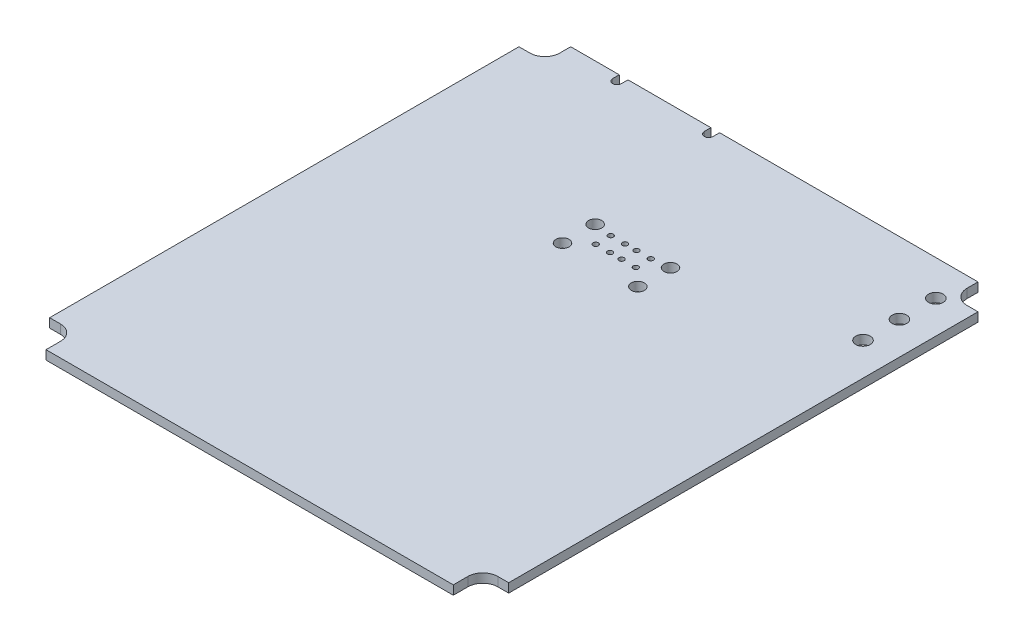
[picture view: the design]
ISO-10303-21;
HEADER;
FILE_DESCRIPTION(('STEP AP214'),'2;1');
FILE_NAME('part.step','',(''),(''),'','','');
FILE_SCHEMA(('AUTOMOTIVE_DESIGN { 1 0 10303 214 1 1 1 1 }'));
ENDSEC;
DATA;
#1=APPLICATION_CONTEXT('core data for automotive mechanical design processes');
#2=APPLICATION_PROTOCOL_DEFINITION('international standard','automotive_design',2000,#1);
#3=PRODUCT_CONTEXT('',#1,'mechanical');
#4=PRODUCT('Part','Part','',(#3));
#5=PRODUCT_RELATED_PRODUCT_CATEGORY('part','',(#4));
#6=PRODUCT_DEFINITION_FORMATION('','',#4);
#7=PRODUCT_DEFINITION_CONTEXT('part definition',#1,'design');
#8=PRODUCT_DEFINITION('design','',#6,#7);
#9=PRODUCT_DEFINITION_SHAPE('','',#8);
#10=(LENGTH_UNIT() NAMED_UNIT(*) SI_UNIT(.MILLI.,.METRE.));
#11=(NAMED_UNIT(*) PLANE_ANGLE_UNIT() SI_UNIT($,.RADIAN.));
#12=(NAMED_UNIT(*) SI_UNIT($,.STERADIAN.) SOLID_ANGLE_UNIT());
#13=UNCERTAINTY_MEASURE_WITH_UNIT(LENGTH_MEASURE(1.E-05),#10,'distance_accuracy_value','');
#14=(GEOMETRIC_REPRESENTATION_CONTEXT(3) GLOBAL_UNCERTAINTY_ASSIGNED_CONTEXT((#13)) GLOBAL_UNIT_ASSIGNED_CONTEXT((#10,
#11,#12)) REPRESENTATION_CONTEXT('',''));
#15=CARTESIAN_POINT('',(0.,0.,0.));
#16=DIRECTION('',(0.,0.,1.));
#17=DIRECTION('',(1.,0.,0.));
#18=AXIS2_PLACEMENT_3D('',#15,#16,#17);
#19=CARTESIAN_POINT('',(-39.99992,0.,45.72));
#20=DIRECTION('',(0.,1.,0.));
#21=DIRECTION('',(0.,0.,1.));
#22=AXIS2_PLACEMENT_3D('',#19,#20,#21);
#23=PLANE('',#22);
#24=DIRECTION('',(1.,0.,0.));
#25=VECTOR('',#24,1.);
#26=CARTESIAN_POINT('',(38.09492,0.,-41.2115));
#27=LINE('',#26,#25);
#28=CARTESIAN_POINT('',(38.09492,0.,-41.2115));
#29=VERTEX_POINT('',#28);
#30=CARTESIAN_POINT('',(39.99992,0.,-41.2115));
#31=VERTEX_POINT('',#30);
#32=EDGE_CURVE('E212',#29,#31,#27,.T.);
#33=ORIENTED_EDGE('',*,*,#32,.T.);
#34=DIRECTION('',(0.,0.,1.));
#35=VECTOR('',#34,1.);
#36=CARTESIAN_POINT('',(39.99992,0.,-45.72));
#37=LINE('',#36,#35);
#38=CARTESIAN_POINT('',(39.99992,0.,40.5765));
#39=VERTEX_POINT('',#38);
#40=EDGE_CURVE('E206',#31,#39,#37,.T.);
#41=ORIENTED_EDGE('',*,*,#40,.T.);
#42=DIRECTION('',(-1.,0.,0.));
#43=VECTOR('',#42,1.);
#44=CARTESIAN_POINT('',(44.3342036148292,0.,40.5765));
#45=LINE('',#44,#43);
#46=CARTESIAN_POINT('',(38.09492,0.,40.5765));
#47=VERTEX_POINT('',#46);
#48=EDGE_CURVE('E216',#39,#47,#45,.T.);
#49=ORIENTED_EDGE('',*,*,#48,.T.);
#50=CARTESIAN_POINT('',(38.09492,0.,43.18));
#51=DIRECTION('',(0.,1.,0.));
#52=DIRECTION('',(0.,0.,1.));
#53=AXIS2_PLACEMENT_3D('',#50,#51,#52);
#54=CIRCLE('',#53,2.6035);
#55=CARTESIAN_POINT('',(35.49142,0.,43.18));
#56=VERTEX_POINT('',#55);
#57=EDGE_CURVE('E367',#47,#56,#54,.T.);
#58=ORIENTED_EDGE('',*,*,#57,.T.);
#59=DIRECTION('',(0.,0.,1.));
#60=VECTOR('',#59,1.);
#61=CARTESIAN_POINT('',(35.49142,0.,43.18));
#62=LINE('',#61,#60);
#63=CARTESIAN_POINT('',(35.49142,0.,45.72));
#64=VERTEX_POINT('',#63);
#65=EDGE_CURVE('E221',#56,#64,#62,.T.);
#66=ORIENTED_EDGE('',*,*,#65,.T.);
#67=DIRECTION('',(-1.,0.,0.));
#68=VECTOR('',#67,1.);
#69=CARTESIAN_POINT('',(-39.99992,0.,45.72));
#70=LINE('',#69,#68);
#71=CARTESIAN_POINT('',(-35.49142,0.,45.72));
#72=VERTEX_POINT('',#71);
#73=EDGE_CURVE('E224',#64,#72,#70,.T.);
#74=ORIENTED_EDGE('',*,*,#73,.T.);
#75=DIRECTION('',(0.,0.,-1.));
#76=VECTOR('',#75,1.);
#77=CARTESIAN_POINT('',(-35.49142,0.,43.18));
#78=LINE('',#77,#76);
#79=CARTESIAN_POINT('',(-35.49142,0.,43.18));
#80=VERTEX_POINT('',#79);
#81=EDGE_CURVE('E232',#72,#80,#78,.T.);
#82=ORIENTED_EDGE('',*,*,#81,.T.);
#83=CARTESIAN_POINT('',(-38.09492,0.,43.18));
#84=DIRECTION('',(0.,1.,0.));
#85=DIRECTION('',(0.,0.,1.));
#86=AXIS2_PLACEMENT_3D('',#83,#84,#85);
#87=CIRCLE('',#86,2.6035);
#88=CARTESIAN_POINT('',(-38.09492,0.,40.5765));
#89=VERTEX_POINT('',#88);
#90=EDGE_CURVE('E369',#80,#89,#87,.T.);
#91=ORIENTED_EDGE('',*,*,#90,.T.);
#92=DIRECTION('',(-1.,0.,0.));
#93=VECTOR('',#92,1.);
#94=CARTESIAN_POINT('',(-43.8329095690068,0.,40.5765));
#95=LINE('',#94,#93);
#96=CARTESIAN_POINT('',(-39.99992,0.,40.5765));
#97=VERTEX_POINT('',#96);
#98=EDGE_CURVE('E238',#89,#97,#95,.T.);
#99=ORIENTED_EDGE('',*,*,#98,.T.);
#100=DIRECTION('',(0.,0.,-1.));
#101=VECTOR('',#100,1.);
#102=CARTESIAN_POINT('',(-39.99992,0.,-45.72));
#103=LINE('',#102,#101);
#104=CARTESIAN_POINT('',(-39.99992,0.,-41.2115));
#105=VERTEX_POINT('',#104);
#106=EDGE_CURVE('E241',#97,#105,#103,.T.);
#107=ORIENTED_EDGE('',*,*,#106,.T.);
#108=DIRECTION('',(1.,0.,0.));
#109=VECTOR('',#108,1.);
#110=CARTESIAN_POINT('',(-38.09492,0.,-41.2115));
#111=LINE('',#110,#109);
#112=CARTESIAN_POINT('',(-38.09492,0.,-41.2115));
#113=VERTEX_POINT('',#112);
#114=EDGE_CURVE('E249',#105,#113,#111,.T.);
#115=ORIENTED_EDGE('',*,*,#114,.T.);
#116=CARTESIAN_POINT('',(-38.09492,0.,-43.815));
#117=DIRECTION('',(0.,1.,0.));
#118=DIRECTION('',(0.,0.,1.));
#119=AXIS2_PLACEMENT_3D('',#116,#117,#118);
#120=CIRCLE('',#119,2.6035);
#121=CARTESIAN_POINT('',(-35.49142,0.,-43.815));
#122=VERTEX_POINT('',#121);
#123=EDGE_CURVE('E371',#113,#122,#120,.T.);
#124=ORIENTED_EDGE('',*,*,#123,.T.);
#125=DIRECTION('',(0.,0.,-1.));
#126=VECTOR('',#125,1.);
#127=CARTESIAN_POINT('',(-35.49142,0.,-49.0443285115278));
#128=LINE('',#127,#126);
#129=CARTESIAN_POINT('',(-35.49142,0.,-45.72));
#130=VERTEX_POINT('',#129);
#131=EDGE_CURVE('E255',#122,#130,#128,.T.);
#132=ORIENTED_EDGE('',*,*,#131,.T.);
#133=DIRECTION('',(1.,0.,0.));
#134=VECTOR('',#133,1.);
#135=CARTESIAN_POINT('',(-39.99992,0.,-45.72));
#136=LINE('',#135,#134);
#137=CARTESIAN_POINT('',(-27.02814,0.,-45.72));
#138=VERTEX_POINT('',#137);
#139=EDGE_CURVE('E261',#130,#138,#136,.T.);
#140=ORIENTED_EDGE('',*,*,#139,.T.);
#141=DIRECTION('',(0.,0.,1.));
#142=VECTOR('',#141,1.);
#143=CARTESIAN_POINT('',(-27.02814,0.,-48.26));
#144=LINE('',#143,#142);
#145=CARTESIAN_POINT('',(-27.02814,0.,-44.577));
#146=VERTEX_POINT('',#145);
#147=EDGE_CURVE('E266',#138,#146,#144,.T.);
#148=ORIENTED_EDGE('',*,*,#147,.T.);
#149=CARTESIAN_POINT('',(-26.26614,0.,-44.577));
#150=DIRECTION('',(0.,1.,0.));
#151=DIRECTION('',(0.,0.,1.));
#152=AXIS2_PLACEMENT_3D('',#149,#150,#151);
#153=CIRCLE('',#152,0.761999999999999);
#154=CARTESIAN_POINT('',(-25.50414,0.,-44.577));
#155=VERTEX_POINT('',#154);
#156=EDGE_CURVE('E268',#146,#155,#153,.T.);
#157=ORIENTED_EDGE('',*,*,#156,.T.);
#158=DIRECTION('',(0.,0.,-1.));
#159=VECTOR('',#158,1.);
#160=CARTESIAN_POINT('',(-25.50414,0.,-48.26));
#161=LINE('',#160,#159);
#162=CARTESIAN_POINT('',(-25.50414,0.,-45.72));
#163=VERTEX_POINT('',#162);
#164=EDGE_CURVE('E271',#155,#163,#161,.T.);
#165=ORIENTED_EDGE('',*,*,#164,.T.);
#166=DIRECTION('',(1.,0.,0.));
#167=VECTOR('',#166,1.);
#168=CARTESIAN_POINT('',(-39.99992,0.,-45.72));
#169=LINE('',#168,#167);
#170=CARTESIAN_POINT('',(-11.06424,0.,-45.72));
#171=VERTEX_POINT('',#170);
#172=EDGE_CURVE('E277',#163,#171,#169,.T.);
#173=ORIENTED_EDGE('',*,*,#172,.T.);
#174=DIRECTION('',(0.,0.,1.));
#175=VECTOR('',#174,1.);
#176=CARTESIAN_POINT('',(-11.06424,0.,-48.26));
#177=LINE('',#176,#175);
#178=CARTESIAN_POINT('',(-11.06424,0.,-44.577));
#179=VERTEX_POINT('',#178);
#180=EDGE_CURVE('E282',#171,#179,#177,.T.);
#181=ORIENTED_EDGE('',*,*,#180,.T.);
#182=CARTESIAN_POINT('',(-10.30224,0.,-44.577));
#183=DIRECTION('',(0.,1.,0.));
#184=DIRECTION('',(0.,0.,1.));
#185=AXIS2_PLACEMENT_3D('',#182,#183,#184);
#186=CIRCLE('',#185,0.761999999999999);
#187=CARTESIAN_POINT('',(-9.54024,0.,-44.577));
#188=VERTEX_POINT('',#187);
#189=EDGE_CURVE('E284',#179,#188,#186,.T.);
#190=ORIENTED_EDGE('',*,*,#189,.T.);
#191=DIRECTION('',(0.,0.,-1.));
#192=VECTOR('',#191,1.);
#193=CARTESIAN_POINT('',(-9.54024,0.,-48.26));
#194=LINE('',#193,#192);
#195=CARTESIAN_POINT('',(-9.54024,0.,-45.72));
#196=VERTEX_POINT('',#195);
#197=EDGE_CURVE('E287',#188,#196,#194,.T.);
#198=ORIENTED_EDGE('',*,*,#197,.T.);
#199=DIRECTION('',(1.,0.,0.));
#200=VECTOR('',#199,1.);
#201=CARTESIAN_POINT('',(-39.99992,0.,-45.72));
#202=LINE('',#201,#200);
#203=CARTESIAN_POINT('',(35.49142,0.,-45.72));
#204=VERTEX_POINT('',#203);
#205=EDGE_CURVE('E192',#196,#204,#202,.T.);
#206=ORIENTED_EDGE('',*,*,#205,.T.);
#207=DIRECTION('',(0.,0.,1.));
#208=VECTOR('',#207,1.);
#209=CARTESIAN_POINT('',(35.49142,0.,-49.0443285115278));
#210=LINE('',#209,#208);
#211=CARTESIAN_POINT('',(35.49142,0.,-43.815));
#212=VERTEX_POINT('',#211);
#213=EDGE_CURVE('E189',#204,#212,#210,.T.);
#214=ORIENTED_EDGE('',*,*,#213,.T.);
#215=CARTESIAN_POINT('',(38.09492,0.,-43.815));
#216=DIRECTION('',(0.,1.,0.));
#217=DIRECTION('',(0.,0.,1.));
#218=AXIS2_PLACEMENT_3D('',#215,#216,#217);
#219=CIRCLE('',#218,2.6035);
#220=EDGE_CURVE('E176',#212,#29,#219,.T.);
#221=ORIENTED_EDGE('',*,*,#220,.T.);
#222=EDGE_LOOP('',(#33,#41,#49,#58,#66,#74,#82,#91,#99,#107,#115,#124,#132,#140,#148,#157,#165,
#173,#181,#190,#198,#206,#214,#221));
#223=FACE_BOUND('',#222,.T.);
#224=CARTESIAN_POINT('',(34.2899999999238,0.,-26.87955));
#225=DIRECTION('',(0.,1.,0.));
#226=DIRECTION('',(0.,0.,1.));
#227=AXIS2_PLACEMENT_3D('',#224,#225,#226);
#228=CIRCLE('',#227,1.27);
#229=CARTESIAN_POINT('',(34.2899999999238,0.,-25.60955));
#230=VERTEX_POINT('',#229);
#231=EDGE_CURVE('E186',#230,#230,#228,.T.);
#232=ORIENTED_EDGE('',*,*,#231,.T.);
#233=EDGE_LOOP('',(#232));
#234=FACE_BOUND('',#233,.T.);
#235=CARTESIAN_POINT('',(34.2899999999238,0.,-33.22955));
#236=DIRECTION('',(0.,1.,0.));
#237=DIRECTION('',(0.,0.,1.));
#238=AXIS2_PLACEMENT_3D('',#235,#236,#237);
#239=CIRCLE('',#238,1.27);
#240=CARTESIAN_POINT('',(34.2899999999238,0.,-31.95955));
#241=VERTEX_POINT('',#240);
#242=EDGE_CURVE('E379',#241,#241,#239,.T.);
#243=ORIENTED_EDGE('',*,*,#242,.T.);
#244=EDGE_LOOP('',(#243));
#245=FACE_BOUND('',#244,.T.);
#246=CARTESIAN_POINT('',(34.2899999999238,0.,-39.57955));
#247=DIRECTION('',(0.,1.,0.));
#248=DIRECTION('',(0.,0.,1.));
#249=AXIS2_PLACEMENT_3D('',#246,#247,#248);
#250=CIRCLE('',#249,1.27);
#251=CARTESIAN_POINT('',(34.2899999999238,0.,-38.30955));
#252=VERTEX_POINT('',#251);
#253=EDGE_CURVE('E382',#252,#252,#250,.T.);
#254=ORIENTED_EDGE('',*,*,#253,.T.);
#255=EDGE_LOOP('',(#254));
#256=FACE_BOUND('',#255,.T.);
#257=CARTESIAN_POINT('',(-6.5659,0.,-21.0566));
#258=DIRECTION('',(0.,1.,0.));
#259=DIRECTION('',(0.,0.,1.));
#260=AXIS2_PLACEMENT_3D('',#257,#258,#259);
#261=CIRCLE('',#260,1.143);
#262=CARTESIAN_POINT('',(-6.5659,0.,-19.9136));
#263=VERTEX_POINT('',#262);
#264=EDGE_CURVE('E385',#263,#263,#261,.T.);
#265=ORIENTED_EDGE('',*,*,#264,.T.);
#266=EDGE_LOOP('',(#265));
#267=FACE_BOUND('',#266,.T.);
#268=CARTESIAN_POINT('',(-6.5659,0.,-15.367));
#269=DIRECTION('',(0.,1.,0.));
#270=DIRECTION('',(0.,0.,1.));
#271=AXIS2_PLACEMENT_3D('',#268,#269,#270);
#272=CIRCLE('',#271,1.143);
#273=CARTESIAN_POINT('',(-6.5659,0.,-14.224));
#274=VERTEX_POINT('',#273);
#275=EDGE_CURVE('E388',#274,#274,#272,.T.);
#276=ORIENTED_EDGE('',*,*,#275,.T.);
#277=EDGE_LOOP('',(#276));
#278=FACE_BOUND('',#277,.T.);
#279=CARTESIAN_POINT('',(6.5659,0.,-15.367));
#280=DIRECTION('',(0.,1.,0.));
#281=DIRECTION('',(0.,0.,1.));
#282=AXIS2_PLACEMENT_3D('',#279,#280,#281);
#283=CIRCLE('',#282,1.143);
#284=CARTESIAN_POINT('',(6.5659,0.,-14.224));
#285=VERTEX_POINT('',#284);
#286=EDGE_CURVE('E391',#285,#285,#283,.T.);
#287=ORIENTED_EDGE('',*,*,#286,.T.);
#288=EDGE_LOOP('',(#287));
#289=FACE_BOUND('',#288,.T.);
#290=CARTESIAN_POINT('',(6.5659,0.,-21.0566));
#291=DIRECTION('',(0.,1.,0.));
#292=DIRECTION('',(0.,0.,1.));
#293=AXIS2_PLACEMENT_3D('',#290,#291,#292);
#294=CIRCLE('',#293,1.143);
#295=CARTESIAN_POINT('',(6.5659,0.,-19.9136));
#296=VERTEX_POINT('',#295);
#297=EDGE_CURVE('E394',#296,#296,#294,.T.);
#298=ORIENTED_EDGE('',*,*,#297,.T.);
#299=EDGE_LOOP('',(#298));
#300=FACE_BOUND('',#299,.T.);
#301=CARTESIAN_POINT('',(-3.4925,0.,-18.0848));
#302=DIRECTION('',(0.,1.,0.));
#303=DIRECTION('',(0.,0.,1.));
#304=AXIS2_PLACEMENT_3D('',#301,#302,#303);
#305=CIRCLE('',#304,0.457200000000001);
#306=CARTESIAN_POINT('',(-3.4925,0.,-17.6276));
#307=VERTEX_POINT('',#306);
#308=EDGE_CURVE('E397',#307,#307,#305,.T.);
#309=ORIENTED_EDGE('',*,*,#308,.T.);
#310=EDGE_LOOP('',(#309));
#311=FACE_BOUND('',#310,.T.);
#312=CARTESIAN_POINT('',(-1.0033,0.,-18.0848));
#313=DIRECTION('',(0.,1.,0.));
#314=DIRECTION('',(0.,0.,1.));
#315=AXIS2_PLACEMENT_3D('',#312,#313,#314);
#316=CIRCLE('',#315,0.457200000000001);
#317=CARTESIAN_POINT('',(-1.0033,0.,-17.6276));
#318=VERTEX_POINT('',#317);
#319=EDGE_CURVE('E400',#318,#318,#316,.T.);
#320=ORIENTED_EDGE('',*,*,#319,.T.);
#321=EDGE_LOOP('',(#320));
#322=FACE_BOUND('',#321,.T.);
#323=CARTESIAN_POINT('',(1.0033,0.,-18.0848));
#324=DIRECTION('',(0.,1.,0.));
#325=DIRECTION('',(0.,0.,1.));
#326=AXIS2_PLACEMENT_3D('',#323,#324,#325);
#327=CIRCLE('',#326,0.457200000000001);
#328=CARTESIAN_POINT('',(1.0033,0.,-17.6276));
#329=VERTEX_POINT('',#328);
#330=EDGE_CURVE('E403',#329,#329,#327,.T.);
#331=ORIENTED_EDGE('',*,*,#330,.T.);
#332=EDGE_LOOP('',(#331));
#333=FACE_BOUND('',#332,.T.);
#334=CARTESIAN_POINT('',(3.4925,0.,-18.0848));
#335=DIRECTION('',(0.,1.,0.));
#336=DIRECTION('',(0.,0.,1.));
#337=AXIS2_PLACEMENT_3D('',#334,#335,#336);
#338=CIRCLE('',#337,0.457200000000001);
#339=CARTESIAN_POINT('',(3.4925,0.,-17.6276));
#340=VERTEX_POINT('',#339);
#341=EDGE_CURVE('E406',#340,#340,#338,.T.);
#342=ORIENTED_EDGE('',*,*,#341,.T.);
#343=EDGE_LOOP('',(#342));
#344=FACE_BOUND('',#343,.T.);
#345=CARTESIAN_POINT('',(3.4925,0.,-20.701));
#346=DIRECTION('',(0.,1.,0.));
#347=DIRECTION('',(0.,0.,1.));
#348=AXIS2_PLACEMENT_3D('',#345,#346,#347);
#349=CIRCLE('',#348,0.457200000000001);
#350=CARTESIAN_POINT('',(3.4925,0.,-20.2438));
#351=VERTEX_POINT('',#350);
#352=EDGE_CURVE('E409',#351,#351,#349,.T.);
#353=ORIENTED_EDGE('',*,*,#352,.T.);
#354=EDGE_LOOP('',(#353));
#355=FACE_BOUND('',#354,.T.);
#356=CARTESIAN_POINT('',(1.0033,0.,-20.701));
#357=DIRECTION('',(0.,1.,0.));
#358=DIRECTION('',(0.,0.,1.));
#359=AXIS2_PLACEMENT_3D('',#356,#357,#358);
#360=CIRCLE('',#359,0.457200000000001);
#361=CARTESIAN_POINT('',(1.0033,0.,-20.2438));
#362=VERTEX_POINT('',#361);
#363=EDGE_CURVE('E412',#362,#362,#360,.T.);
#364=ORIENTED_EDGE('',*,*,#363,.T.);
#365=EDGE_LOOP('',(#364));
#366=FACE_BOUND('',#365,.T.);
#367=CARTESIAN_POINT('',(-3.4925,0.,-20.701));
#368=DIRECTION('',(0.,1.,0.));
#369=DIRECTION('',(0.,0.,1.));
#370=AXIS2_PLACEMENT_3D('',#367,#368,#369);
#371=CIRCLE('',#370,0.457200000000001);
#372=CARTESIAN_POINT('',(-3.4925,0.,-20.2438));
#373=VERTEX_POINT('',#372);
#374=EDGE_CURVE('E414',#373,#373,#371,.T.);
#375=ORIENTED_EDGE('',*,*,#374,.T.);
#376=EDGE_LOOP('',(#375));
#377=FACE_BOUND('',#376,.T.);
#378=CARTESIAN_POINT('',(-1.0033,0.,-20.701));
#379=DIRECTION('',(0.,1.,0.));
#380=DIRECTION('',(0.,0.,1.));
#381=AXIS2_PLACEMENT_3D('',#378,#379,#380);
#382=CIRCLE('',#381,0.457200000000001);
#383=CARTESIAN_POINT('',(-1.0033,0.,-20.2438));
#384=VERTEX_POINT('',#383);
#385=EDGE_CURVE('E20',#384,#384,#382,.T.);
#386=ORIENTED_EDGE('',*,*,#385,.T.);
#387=EDGE_LOOP('',(#386));
#388=FACE_BOUND('',#387,.T.);
#389=ADVANCED_FACE('F17',(#223,#234,#245,#256,#267,#278,#289,#300,#311,#322,#333,#344,#355,#366,
#377,#388),#23,.F.);
#390=CARTESIAN_POINT('',(-1.0033,-3.5052,-20.701));
#391=DIRECTION('',(0.,1.,0.));
#392=DIRECTION('',(0.,0.,1.));
#393=AXIS2_PLACEMENT_3D('',#390,#391,#392);
#394=CYLINDRICAL_SURFACE('',#393,0.457200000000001);
#395=ORIENTED_EDGE('',*,*,#385,.F.);
#396=EDGE_LOOP('',(#395));
#397=FACE_BOUND('',#396,.T.);
#398=CARTESIAN_POINT('',(-1.0033,1.5748,-20.701));
#399=DIRECTION('',(0.,1.,0.));
#400=DIRECTION('',(0.,0.,1.));
#401=AXIS2_PLACEMENT_3D('',#398,#399,#400);
#402=CIRCLE('',#401,0.457200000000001);
#403=CARTESIAN_POINT('',(-1.0033,1.5748,-20.2438));
#404=VERTEX_POINT('',#403);
#405=EDGE_CURVE('E364',#404,#404,#402,.F.);
#406=ORIENTED_EDGE('',*,*,#405,.F.);
#407=EDGE_LOOP('',(#406));
#408=FACE_BOUND('',#407,.T.);
#409=ADVANCED_FACE('F422',(#397,#408),#394,.F.);
#410=CARTESIAN_POINT('',(-3.4925,-3.5052,-20.701));
#411=DIRECTION('',(0.,1.,0.));
#412=DIRECTION('',(0.,0.,1.));
#413=AXIS2_PLACEMENT_3D('',#410,#411,#412);
#414=CYLINDRICAL_SURFACE('',#413,0.457200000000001);
#415=ORIENTED_EDGE('',*,*,#374,.F.);
#416=EDGE_LOOP('',(#415));
#417=FACE_BOUND('',#416,.T.);
#418=CARTESIAN_POINT('',(-3.4925,1.5748,-20.701));
#419=DIRECTION('',(0.,1.,0.));
#420=DIRECTION('',(0.,0.,1.));
#421=AXIS2_PLACEMENT_3D('',#418,#419,#420);
#422=CIRCLE('',#421,0.457200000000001);
#423=CARTESIAN_POINT('',(-3.4925,1.5748,-20.2438));
#424=VERTEX_POINT('',#423);
#425=EDGE_CURVE('E361',#424,#424,#422,.F.);
#426=ORIENTED_EDGE('',*,*,#425,.F.);
#427=EDGE_LOOP('',(#426));
#428=FACE_BOUND('',#427,.T.);
#429=ADVANCED_FACE('F425',(#417,#428),#414,.F.);
#430=CARTESIAN_POINT('',(1.0033,-3.5052,-20.701));
#431=DIRECTION('',(0.,1.,0.));
#432=DIRECTION('',(0.,0.,1.));
#433=AXIS2_PLACEMENT_3D('',#430,#431,#432);
#434=CYLINDRICAL_SURFACE('',#433,0.457200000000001);
#435=ORIENTED_EDGE('',*,*,#363,.F.);
#436=EDGE_LOOP('',(#435));
#437=FACE_BOUND('',#436,.T.);
#438=CARTESIAN_POINT('',(1.0033,1.5748,-20.701));
#439=DIRECTION('',(0.,1.,0.));
#440=DIRECTION('',(0.,0.,1.));
#441=AXIS2_PLACEMENT_3D('',#438,#439,#440);
#442=CIRCLE('',#441,0.457200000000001);
#443=CARTESIAN_POINT('',(1.0033,1.5748,-20.2438));
#444=VERTEX_POINT('',#443);
#445=EDGE_CURVE('E358',#444,#444,#442,.F.);
#446=ORIENTED_EDGE('',*,*,#445,.F.);
#447=EDGE_LOOP('',(#446));
#448=FACE_BOUND('',#447,.T.);
#449=ADVANCED_FACE('F576',(#437,#448),#434,.F.);
#450=CARTESIAN_POINT('',(3.4925,-3.5052,-20.701));
#451=DIRECTION('',(0.,1.,0.));
#452=DIRECTION('',(0.,0.,1.));
#453=AXIS2_PLACEMENT_3D('',#450,#451,#452);
#454=CYLINDRICAL_SURFACE('',#453,0.457200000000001);
#455=ORIENTED_EDGE('',*,*,#352,.F.);
#456=EDGE_LOOP('',(#455));
#457=FACE_BOUND('',#456,.T.);
#458=CARTESIAN_POINT('',(3.4925,1.5748,-20.701));
#459=DIRECTION('',(0.,1.,0.));
#460=DIRECTION('',(0.,0.,1.));
#461=AXIS2_PLACEMENT_3D('',#458,#459,#460);
#462=CIRCLE('',#461,0.457200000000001);
#463=CARTESIAN_POINT('',(3.4925,1.5748,-20.2438));
#464=VERTEX_POINT('',#463);
#465=EDGE_CURVE('E355',#464,#464,#462,.F.);
#466=ORIENTED_EDGE('',*,*,#465,.F.);
#467=EDGE_LOOP('',(#466));
#468=FACE_BOUND('',#467,.T.);
#469=ADVANCED_FACE('F572',(#457,#468),#454,.F.);
#470=CARTESIAN_POINT('',(3.4925,-3.5052,-18.0848));
#471=DIRECTION('',(0.,1.,0.));
#472=DIRECTION('',(0.,0.,1.));
#473=AXIS2_PLACEMENT_3D('',#470,#471,#472);
#474=CYLINDRICAL_SURFACE('',#473,0.457200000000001);
#475=ORIENTED_EDGE('',*,*,#341,.F.);
#476=EDGE_LOOP('',(#475));
#477=FACE_BOUND('',#476,.T.);
#478=CARTESIAN_POINT('',(3.4925,1.5748,-18.0848));
#479=DIRECTION('',(0.,1.,0.));
#480=DIRECTION('',(0.,0.,1.));
#481=AXIS2_PLACEMENT_3D('',#478,#479,#480);
#482=CIRCLE('',#481,0.457200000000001);
#483=CARTESIAN_POINT('',(3.4925,1.5748,-17.6276));
#484=VERTEX_POINT('',#483);
#485=EDGE_CURVE('E352',#484,#484,#482,.F.);
#486=ORIENTED_EDGE('',*,*,#485,.F.);
#487=EDGE_LOOP('',(#486));
#488=FACE_BOUND('',#487,.T.);
#489=ADVANCED_FACE('F568',(#477,#488),#474,.F.);
#490=CARTESIAN_POINT('',(1.0033,-3.5052,-18.0848));
#491=DIRECTION('',(0.,1.,0.));
#492=DIRECTION('',(0.,0.,1.));
#493=AXIS2_PLACEMENT_3D('',#490,#491,#492);
#494=CYLINDRICAL_SURFACE('',#493,0.457200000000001);
#495=ORIENTED_EDGE('',*,*,#330,.F.);
#496=EDGE_LOOP('',(#495));
#497=FACE_BOUND('',#496,.T.);
#498=CARTESIAN_POINT('',(1.0033,1.5748,-18.0848));
#499=DIRECTION('',(0.,1.,0.));
#500=DIRECTION('',(0.,0.,1.));
#501=AXIS2_PLACEMENT_3D('',#498,#499,#500);
#502=CIRCLE('',#501,0.457200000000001);
#503=CARTESIAN_POINT('',(1.0033,1.5748,-17.6276));
#504=VERTEX_POINT('',#503);
#505=EDGE_CURVE('E349',#504,#504,#502,.F.);
#506=ORIENTED_EDGE('',*,*,#505,.F.);
#507=EDGE_LOOP('',(#506));
#508=FACE_BOUND('',#507,.T.);
#509=ADVANCED_FACE('F564',(#497,#508),#494,.F.);
#510=CARTESIAN_POINT('',(-1.0033,-3.5052,-18.0848));
#511=DIRECTION('',(0.,1.,0.));
#512=DIRECTION('',(0.,0.,1.));
#513=AXIS2_PLACEMENT_3D('',#510,#511,#512);
#514=CYLINDRICAL_SURFACE('',#513,0.457200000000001);
#515=ORIENTED_EDGE('',*,*,#319,.F.);
#516=EDGE_LOOP('',(#515));
#517=FACE_BOUND('',#516,.T.);
#518=CARTESIAN_POINT('',(-1.0033,1.5748,-18.0848));
#519=DIRECTION('',(0.,1.,0.));
#520=DIRECTION('',(0.,0.,1.));
#521=AXIS2_PLACEMENT_3D('',#518,#519,#520);
#522=CIRCLE('',#521,0.457200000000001);
#523=CARTESIAN_POINT('',(-1.0033,1.5748,-17.6276));
#524=VERTEX_POINT('',#523);
#525=EDGE_CURVE('E346',#524,#524,#522,.F.);
#526=ORIENTED_EDGE('',*,*,#525,.F.);
#527=EDGE_LOOP('',(#526));
#528=FACE_BOUND('',#527,.T.);
#529=ADVANCED_FACE('F560',(#517,#528),#514,.F.);
#530=CARTESIAN_POINT('',(-3.4925,-3.5052,-18.0848));
#531=DIRECTION('',(0.,1.,0.));
#532=DIRECTION('',(0.,0.,1.));
#533=AXIS2_PLACEMENT_3D('',#530,#531,#532);
#534=CYLINDRICAL_SURFACE('',#533,0.457200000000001);
#535=ORIENTED_EDGE('',*,*,#308,.F.);
#536=EDGE_LOOP('',(#535));
#537=FACE_BOUND('',#536,.T.);
#538=CARTESIAN_POINT('',(-3.4925,1.5748,-18.0848));
#539=DIRECTION('',(0.,1.,0.));
#540=DIRECTION('',(0.,0.,1.));
#541=AXIS2_PLACEMENT_3D('',#538,#539,#540);
#542=CIRCLE('',#541,0.457200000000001);
#543=CARTESIAN_POINT('',(-3.4925,1.5748,-17.6276));
#544=VERTEX_POINT('',#543);
#545=EDGE_CURVE('E343',#544,#544,#542,.F.);
#546=ORIENTED_EDGE('',*,*,#545,.F.);
#547=EDGE_LOOP('',(#546));
#548=FACE_BOUND('',#547,.T.);
#549=ADVANCED_FACE('F556',(#537,#548),#534,.F.);
#550=CARTESIAN_POINT('',(6.5659,-3.5052,-21.0566));
#551=DIRECTION('',(0.,1.,0.));
#552=DIRECTION('',(0.,0.,1.));
#553=AXIS2_PLACEMENT_3D('',#550,#551,#552);
#554=CYLINDRICAL_SURFACE('',#553,1.143);
#555=ORIENTED_EDGE('',*,*,#297,.F.);
#556=EDGE_LOOP('',(#555));
#557=FACE_BOUND('',#556,.T.);
#558=CARTESIAN_POINT('',(6.5659,1.5748,-21.0566));
#559=DIRECTION('',(0.,1.,0.));
#560=DIRECTION('',(0.,0.,1.));
#561=AXIS2_PLACEMENT_3D('',#558,#559,#560);
#562=CIRCLE('',#561,1.143);
#563=CARTESIAN_POINT('',(6.5659,1.5748,-19.9136));
#564=VERTEX_POINT('',#563);
#565=EDGE_CURVE('E340',#564,#564,#562,.F.);
#566=ORIENTED_EDGE('',*,*,#565,.F.);
#567=EDGE_LOOP('',(#566));
#568=FACE_BOUND('',#567,.T.);
#569=ADVANCED_FACE('F552',(#557,#568),#554,.F.);
#570=CARTESIAN_POINT('',(6.5659,-3.5052,-15.367));
#571=DIRECTION('',(0.,1.,0.));
#572=DIRECTION('',(0.,0.,1.));
#573=AXIS2_PLACEMENT_3D('',#570,#571,#572);
#574=CYLINDRICAL_SURFACE('',#573,1.143);
#575=ORIENTED_EDGE('',*,*,#286,.F.);
#576=EDGE_LOOP('',(#575));
#577=FACE_BOUND('',#576,.T.);
#578=CARTESIAN_POINT('',(6.5659,1.5748,-15.367));
#579=DIRECTION('',(0.,1.,0.));
#580=DIRECTION('',(0.,0.,1.));
#581=AXIS2_PLACEMENT_3D('',#578,#579,#580);
#582=CIRCLE('',#581,1.143);
#583=CARTESIAN_POINT('',(6.5659,1.5748,-14.224));
#584=VERTEX_POINT('',#583);
#585=EDGE_CURVE('E337',#584,#584,#582,.F.);
#586=ORIENTED_EDGE('',*,*,#585,.F.);
#587=EDGE_LOOP('',(#586));
#588=FACE_BOUND('',#587,.T.);
#589=ADVANCED_FACE('F548',(#577,#588),#574,.F.);
#590=CARTESIAN_POINT('',(-6.5659,-3.5052,-15.367));
#591=DIRECTION('',(0.,1.,0.));
#592=DIRECTION('',(0.,0.,1.));
#593=AXIS2_PLACEMENT_3D('',#590,#591,#592);
#594=CYLINDRICAL_SURFACE('',#593,1.143);
#595=ORIENTED_EDGE('',*,*,#275,.F.);
#596=EDGE_LOOP('',(#595));
#597=FACE_BOUND('',#596,.T.);
#598=CARTESIAN_POINT('',(-6.5659,1.5748,-15.367));
#599=DIRECTION('',(0.,1.,0.));
#600=DIRECTION('',(0.,0.,1.));
#601=AXIS2_PLACEMENT_3D('',#598,#599,#600);
#602=CIRCLE('',#601,1.143);
#603=CARTESIAN_POINT('',(-6.5659,1.5748,-14.224));
#604=VERTEX_POINT('',#603);
#605=EDGE_CURVE('E334',#604,#604,#602,.F.);
#606=ORIENTED_EDGE('',*,*,#605,.F.);
#607=EDGE_LOOP('',(#606));
#608=FACE_BOUND('',#607,.T.);
#609=ADVANCED_FACE('F544',(#597,#608),#594,.F.);
#610=CARTESIAN_POINT('',(-6.5659,-3.5052,-21.0566));
#611=DIRECTION('',(0.,1.,0.));
#612=DIRECTION('',(0.,0.,1.));
#613=AXIS2_PLACEMENT_3D('',#610,#611,#612);
#614=CYLINDRICAL_SURFACE('',#613,1.143);
#615=ORIENTED_EDGE('',*,*,#264,.F.);
#616=EDGE_LOOP('',(#615));
#617=FACE_BOUND('',#616,.T.);
#618=CARTESIAN_POINT('',(-6.5659,1.5748,-21.0566));
#619=DIRECTION('',(0.,1.,0.));
#620=DIRECTION('',(0.,0.,1.));
#621=AXIS2_PLACEMENT_3D('',#618,#619,#620);
#622=CIRCLE('',#621,1.143);
#623=CARTESIAN_POINT('',(-6.5659,1.5748,-19.9136));
#624=VERTEX_POINT('',#623);
#625=EDGE_CURVE('E331',#624,#624,#622,.F.);
#626=ORIENTED_EDGE('',*,*,#625,.F.);
#627=EDGE_LOOP('',(#626));
#628=FACE_BOUND('',#627,.T.);
#629=ADVANCED_FACE('F540',(#617,#628),#614,.F.);
#630=CARTESIAN_POINT('',(34.2899999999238,-0.9652,-39.57955));
#631=DIRECTION('',(0.,1.,0.));
#632=DIRECTION('',(0.,0.,1.));
#633=AXIS2_PLACEMENT_3D('',#630,#631,#632);
#634=CYLINDRICAL_SURFACE('',#633,1.27);
#635=ORIENTED_EDGE('',*,*,#253,.F.);
#636=EDGE_LOOP('',(#635));
#637=FACE_BOUND('',#636,.T.);
#638=CARTESIAN_POINT('',(34.2899999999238,1.5748,-39.57955));
#639=DIRECTION('',(0.,1.,0.));
#640=DIRECTION('',(0.,0.,1.));
#641=AXIS2_PLACEMENT_3D('',#638,#639,#640);
#642=CIRCLE('',#641,1.27);
#643=CARTESIAN_POINT('',(34.2899999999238,1.5748,-38.30955));
#644=VERTEX_POINT('',#643);
#645=EDGE_CURVE('E328',#644,#644,#642,.F.);
#646=ORIENTED_EDGE('',*,*,#645,.F.);
#647=EDGE_LOOP('',(#646));
#648=FACE_BOUND('',#647,.T.);
#649=ADVANCED_FACE('F536',(#637,#648),#634,.F.);
#650=CARTESIAN_POINT('',(34.2899999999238,-0.9652,-33.22955));
#651=DIRECTION('',(0.,1.,0.));
#652=DIRECTION('',(0.,0.,1.));
#653=AXIS2_PLACEMENT_3D('',#650,#651,#652);
#654=CYLINDRICAL_SURFACE('',#653,1.27);
#655=ORIENTED_EDGE('',*,*,#242,.F.);
#656=EDGE_LOOP('',(#655));
#657=FACE_BOUND('',#656,.T.);
#658=CARTESIAN_POINT('',(34.2899999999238,1.5748,-33.22955));
#659=DIRECTION('',(0.,1.,0.));
#660=DIRECTION('',(0.,0.,1.));
#661=AXIS2_PLACEMENT_3D('',#658,#659,#660);
#662=CIRCLE('',#661,1.27);
#663=CARTESIAN_POINT('',(34.2899999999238,1.5748,-31.95955));
#664=VERTEX_POINT('',#663);
#665=EDGE_CURVE('E325',#664,#664,#662,.F.);
#666=ORIENTED_EDGE('',*,*,#665,.F.);
#667=EDGE_LOOP('',(#666));
#668=FACE_BOUND('',#667,.T.);
#669=ADVANCED_FACE('F532',(#657,#668),#654,.F.);
#670=CARTESIAN_POINT('',(34.2899999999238,-0.9652,-26.87955));
#671=DIRECTION('',(0.,1.,0.));
#672=DIRECTION('',(0.,0.,1.));
#673=AXIS2_PLACEMENT_3D('',#670,#671,#672);
#674=CYLINDRICAL_SURFACE('',#673,1.27);
#675=ORIENTED_EDGE('',*,*,#231,.F.);
#676=EDGE_LOOP('',(#675));
#677=FACE_BOUND('',#676,.T.);
#678=CARTESIAN_POINT('',(34.2899999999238,1.5748,-26.87955));
#679=DIRECTION('',(0.,1.,0.));
#680=DIRECTION('',(0.,0.,1.));
#681=AXIS2_PLACEMENT_3D('',#678,#679,#680);
#682=CIRCLE('',#681,1.27);
#683=CARTESIAN_POINT('',(34.2899999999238,1.5748,-25.60955));
#684=VERTEX_POINT('',#683);
#685=EDGE_CURVE('E322',#684,#684,#682,.F.);
#686=ORIENTED_EDGE('',*,*,#685,.F.);
#687=EDGE_LOOP('',(#686));
#688=FACE_BOUND('',#687,.T.);
#689=ADVANCED_FACE('F529',(#677,#688),#674,.F.);
#690=CARTESIAN_POINT('',(38.09492,-0.9652,-43.815));
#691=DIRECTION('',(0.,1.,0.));
#692=DIRECTION('',(0.,0.,1.));
#693=AXIS2_PLACEMENT_3D('',#690,#691,#692);
#694=CYLINDRICAL_SURFACE('',#693,2.6035);
#695=ORIENTED_EDGE('',*,*,#220,.F.);
#696=DIRECTION('',(0.,1.,0.));
#697=VECTOR('',#696,1.);
#698=CARTESIAN_POINT('',(35.49142,-0.9652,-43.815));
#699=LINE('',#698,#697);
#700=CARTESIAN_POINT('',(35.49142,1.5748,-43.815));
#701=VERTEX_POINT('',#700);
#702=EDGE_CURVE('E180',#212,#701,#699,.T.);
#703=ORIENTED_EDGE('',*,*,#702,.T.);
#704=CARTESIAN_POINT('',(38.09492,1.5748,-43.815));
#705=DIRECTION('',(0.,1.,0.));
#706=DIRECTION('',(0.,0.,1.));
#707=AXIS2_PLACEMENT_3D('',#704,#705,#706);
#708=CIRCLE('',#707,2.6035);
#709=CARTESIAN_POINT('',(38.09492,1.5748,-41.2115));
#710=VERTEX_POINT('',#709);
#711=EDGE_CURVE('E320',#710,#701,#708,.F.);
#712=ORIENTED_EDGE('',*,*,#711,.F.);
#713=DIRECTION('',(0.,1.,0.));
#714=VECTOR('',#713,1.);
#715=CARTESIAN_POINT('',(38.09492,-0.9652,-41.2115));
#716=LINE('',#715,#714);
#717=EDGE_CURVE('E183',#710,#29,#716,.F.);
#718=ORIENTED_EDGE('',*,*,#717,.T.);
#719=EDGE_LOOP('',(#695,#703,#712,#718));
#720=FACE_BOUND('',#719,.T.);
#721=ADVANCED_FACE('F178',(#720),#694,.F.);
#722=CARTESIAN_POINT('',(35.49142,-0.9652,-49.0443285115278));
#723=DIRECTION('',(-1.,0.,0.));
#724=DIRECTION('',(0.,0.,1.));
#725=AXIS2_PLACEMENT_3D('',#722,#723,#724);
#726=PLANE('',#725);
#727=DIRECTION('',(0.,1.,0.));
#728=VECTOR('',#727,1.);
#729=CARTESIAN_POINT('',(35.49142,1.5748,-45.72));
#730=LINE('',#729,#728);
#731=CARTESIAN_POINT('',(35.49142,1.5748,-45.72));
#732=VERTEX_POINT('',#731);
#733=EDGE_CURVE('E195',#204,#732,#730,.T.);
#734=ORIENTED_EDGE('',*,*,#733,.T.);
#735=DIRECTION('',(0.,0.,1.));
#736=VECTOR('',#735,1.);
#737=CARTESIAN_POINT('',(35.49142,1.5748,45.72));
#738=LINE('',#737,#736);
#739=EDGE_CURVE('E199',#701,#732,#738,.F.);
#740=ORIENTED_EDGE('',*,*,#739,.F.);
#741=ORIENTED_EDGE('',*,*,#702,.F.);
#742=ORIENTED_EDGE('',*,*,#213,.F.);
#743=EDGE_LOOP('',(#734,#740,#741,#742));
#744=FACE_BOUND('',#743,.T.);
#745=ADVANCED_FACE('F197',(#744),#726,.F.);
#746=CARTESIAN_POINT('',(-39.99992,1.5748,-45.72));
#747=DIRECTION('',(0.,0.,1.));
#748=DIRECTION('',(1.,0.,0.));
#749=AXIS2_PLACEMENT_3D('',#746,#747,#748);
#750=PLANE('',#749);
#751=DIRECTION('',(0.,1.,0.));
#752=VECTOR('',#751,1.);
#753=CARTESIAN_POINT('',(-9.54024,-0.9652,-45.72));
#754=LINE('',#753,#752);
#755=CARTESIAN_POINT('',(-9.54024,1.5748,-45.72));
#756=VERTEX_POINT('',#755);
#757=EDGE_CURVE('E289',#196,#756,#754,.T.);
#758=ORIENTED_EDGE('',*,*,#757,.T.);
#759=DIRECTION('',(1.,0.,0.));
#760=VECTOR('',#759,1.);
#761=CARTESIAN_POINT('',(-39.99992,1.5748,-45.72));
#762=LINE('',#761,#760);
#763=EDGE_CURVE('E821',#732,#756,#762,.F.);
#764=ORIENTED_EDGE('',*,*,#763,.F.);
#765=ORIENTED_EDGE('',*,*,#733,.F.);
#766=ORIENTED_EDGE('',*,*,#205,.F.);
#767=EDGE_LOOP('',(#758,#764,#765,#766));
#768=FACE_BOUND('',#767,.T.);
#769=ADVANCED_FACE('F520',(#768),#750,.F.);
#770=CARTESIAN_POINT('',(-9.54024,-0.9652,-48.26));
#771=DIRECTION('',(1.,0.,0.));
#772=DIRECTION('',(0.,0.,-1.));
#773=AXIS2_PLACEMENT_3D('',#770,#771,#772);
#774=PLANE('',#773);
#775=ORIENTED_EDGE('',*,*,#197,.F.);
#776=DIRECTION('',(0.,1.,0.));
#777=VECTOR('',#776,1.);
#778=CARTESIAN_POINT('',(-9.54024,-0.9652,-44.577));
#779=LINE('',#778,#777);
#780=CARTESIAN_POINT('',(-9.54024,1.5748,-44.577));
#781=VERTEX_POINT('',#780);
#782=EDGE_CURVE('E375',#188,#781,#779,.T.);
#783=ORIENTED_EDGE('',*,*,#782,.T.);
#784=DIRECTION('',(0.,0.,1.));
#785=VECTOR('',#784,1.);
#786=CARTESIAN_POINT('',(-9.54024,1.5748,45.72));
#787=LINE('',#786,#785);
#788=EDGE_CURVE('E319',#756,#781,#787,.T.);
#789=ORIENTED_EDGE('',*,*,#788,.F.);
#790=ORIENTED_EDGE('',*,*,#757,.F.);
#791=EDGE_LOOP('',(#775,#783,#789,#790));
#792=FACE_BOUND('',#791,.T.);
#793=ADVANCED_FACE('F516',(#792),#774,.F.);
#794=CARTESIAN_POINT('',(-10.30224,-0.9652,-44.577));
#795=DIRECTION('',(0.,1.,0.));
#796=DIRECTION('',(0.,0.,1.));
#797=AXIS2_PLACEMENT_3D('',#794,#795,#796);
#798=CYLINDRICAL_SURFACE('',#797,0.761999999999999);
#799=ORIENTED_EDGE('',*,*,#189,.F.);
#800=DIRECTION('',(0.,1.,0.));
#801=VECTOR('',#800,1.);
#802=CARTESIAN_POINT('',(-11.06424,-0.9652,-44.577));
#803=LINE('',#802,#801);
#804=CARTESIAN_POINT('',(-11.06424,1.5748,-44.577));
#805=VERTEX_POINT('',#804);
#806=EDGE_CURVE('E279',#179,#805,#803,.T.);
#807=ORIENTED_EDGE('',*,*,#806,.T.);
#808=CARTESIAN_POINT('',(-10.30224,1.5748,-44.577));
#809=DIRECTION('',(0.,1.,0.));
#810=DIRECTION('',(0.,0.,1.));
#811=AXIS2_PLACEMENT_3D('',#808,#809,#810);
#812=CIRCLE('',#811,0.761999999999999);
#813=EDGE_CURVE('E316',#781,#805,#812,.F.);
#814=ORIENTED_EDGE('',*,*,#813,.F.);
#815=ORIENTED_EDGE('',*,*,#782,.F.);
#816=EDGE_LOOP('',(#799,#807,#814,#815));
#817=FACE_BOUND('',#816,.T.);
#818=ADVANCED_FACE('F512',(#817),#798,.F.);
#819=CARTESIAN_POINT('',(-11.06424,-0.9652,-48.26));
#820=DIRECTION('',(-1.,0.,0.));
#821=DIRECTION('',(0.,0.,1.));
#822=AXIS2_PLACEMENT_3D('',#819,#820,#821);
#823=PLANE('',#822);
#824=ORIENTED_EDGE('',*,*,#180,.F.);
#825=DIRECTION('',(0.,1.,0.));
#826=VECTOR('',#825,1.);
#827=CARTESIAN_POINT('',(-11.06424,1.5748,-45.72));
#828=LINE('',#827,#826);
#829=CARTESIAN_POINT('',(-11.06424,1.5748,-45.72));
#830=VERTEX_POINT('',#829);
#831=EDGE_CURVE('E274',#171,#830,#828,.T.);
#832=ORIENTED_EDGE('',*,*,#831,.T.);
#833=DIRECTION('',(0.,0.,1.));
#834=VECTOR('',#833,1.);
#835=CARTESIAN_POINT('',(-11.06424,1.5748,45.72));
#836=LINE('',#835,#834);
#837=EDGE_CURVE('E318',#805,#830,#836,.F.);
#838=ORIENTED_EDGE('',*,*,#837,.F.);
#839=ORIENTED_EDGE('',*,*,#806,.F.);
#840=EDGE_LOOP('',(#824,#832,#838,#839));
#841=FACE_BOUND('',#840,.T.);
#842=ADVANCED_FACE('F508',(#841),#823,.F.);
#843=CARTESIAN_POINT('',(-39.99992,1.5748,-45.72));
#844=DIRECTION('',(0.,0.,1.));
#845=DIRECTION('',(1.,0.,0.));
#846=AXIS2_PLACEMENT_3D('',#843,#844,#845);
#847=PLANE('',#846);
#848=ORIENTED_EDGE('',*,*,#831,.F.);
#849=ORIENTED_EDGE('',*,*,#172,.F.);
#850=DIRECTION('',(0.,1.,0.));
#851=VECTOR('',#850,1.);
#852=CARTESIAN_POINT('',(-25.50414,-0.9652,-45.72));
#853=LINE('',#852,#851);
#854=CARTESIAN_POINT('',(-25.50414,1.5748,-45.72));
#855=VERTEX_POINT('',#854);
#856=EDGE_CURVE('E273',#163,#855,#853,.T.);
#857=ORIENTED_EDGE('',*,*,#856,.T.);
#858=DIRECTION('',(1.,0.,0.));
#859=VECTOR('',#858,1.);
#860=CARTESIAN_POINT('',(-39.99992,1.5748,-45.72));
#861=LINE('',#860,#859);
#862=EDGE_CURVE('E843',#830,#855,#861,.F.);
#863=ORIENTED_EDGE('',*,*,#862,.F.);
#864=EDGE_LOOP('',(#848,#849,#857,#863));
#865=FACE_BOUND('',#864,.T.);
#866=ADVANCED_FACE('F504',(#865),#847,.F.);
#867=CARTESIAN_POINT('',(-25.50414,-0.9652,-48.26));
#868=DIRECTION('',(1.,0.,0.));
#869=DIRECTION('',(0.,0.,-1.));
#870=AXIS2_PLACEMENT_3D('',#867,#868,#869);
#871=PLANE('',#870);
#872=ORIENTED_EDGE('',*,*,#164,.F.);
#873=DIRECTION('',(0.,1.,0.));
#874=VECTOR('',#873,1.);
#875=CARTESIAN_POINT('',(-25.50414,-0.9652,-44.577));
#876=LINE('',#875,#874);
#877=CARTESIAN_POINT('',(-25.50414,1.5748,-44.577));
#878=VERTEX_POINT('',#877);
#879=EDGE_CURVE('E374',#155,#878,#876,.T.);
#880=ORIENTED_EDGE('',*,*,#879,.T.);
#881=DIRECTION('',(0.,0.,1.));
#882=VECTOR('',#881,1.);
#883=CARTESIAN_POINT('',(-25.50414,1.5748,45.72));
#884=LINE('',#883,#882);
#885=EDGE_CURVE('E315',#855,#878,#884,.T.);
#886=ORIENTED_EDGE('',*,*,#885,.F.);
#887=ORIENTED_EDGE('',*,*,#856,.F.);
#888=EDGE_LOOP('',(#872,#880,#886,#887));
#889=FACE_BOUND('',#888,.T.);
#890=ADVANCED_FACE('F500',(#889),#871,.F.);
#891=CARTESIAN_POINT('',(-26.26614,-0.9652,-44.577));
#892=DIRECTION('',(0.,1.,0.));
#893=DIRECTION('',(0.,0.,1.));
#894=AXIS2_PLACEMENT_3D('',#891,#892,#893);
#895=CYLINDRICAL_SURFACE('',#894,0.761999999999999);
#896=ORIENTED_EDGE('',*,*,#156,.F.);
#897=DIRECTION('',(0.,1.,0.));
#898=VECTOR('',#897,1.);
#899=CARTESIAN_POINT('',(-27.02814,-0.9652,-44.577));
#900=LINE('',#899,#898);
#901=CARTESIAN_POINT('',(-27.02814,1.5748,-44.577));
#902=VERTEX_POINT('',#901);
#903=EDGE_CURVE('E263',#146,#902,#900,.T.);
#904=ORIENTED_EDGE('',*,*,#903,.T.);
#905=CARTESIAN_POINT('',(-26.26614,1.5748,-44.577));
#906=DIRECTION('',(0.,1.,0.));
#907=DIRECTION('',(0.,0.,1.));
#908=AXIS2_PLACEMENT_3D('',#905,#906,#907);
#909=CIRCLE('',#908,0.761999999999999);
#910=EDGE_CURVE('E312',#878,#902,#909,.F.);
#911=ORIENTED_EDGE('',*,*,#910,.F.);
#912=ORIENTED_EDGE('',*,*,#879,.F.);
#913=EDGE_LOOP('',(#896,#904,#911,#912));
#914=FACE_BOUND('',#913,.T.);
#915=ADVANCED_FACE('F496',(#914),#895,.F.);
#916=CARTESIAN_POINT('',(-27.02814,-0.9652,-48.26));
#917=DIRECTION('',(-1.,0.,0.));
#918=DIRECTION('',(0.,0.,1.));
#919=AXIS2_PLACEMENT_3D('',#916,#917,#918);
#920=PLANE('',#919);
#921=ORIENTED_EDGE('',*,*,#147,.F.);
#922=DIRECTION('',(0.,1.,0.));
#923=VECTOR('',#922,1.);
#924=CARTESIAN_POINT('',(-27.02814,1.5748,-45.72));
#925=LINE('',#924,#923);
#926=CARTESIAN_POINT('',(-27.02814,1.5748,-45.72));
#927=VERTEX_POINT('',#926);
#928=EDGE_CURVE('E258',#138,#927,#925,.T.);
#929=ORIENTED_EDGE('',*,*,#928,.T.);
#930=DIRECTION('',(0.,0.,1.));
#931=VECTOR('',#930,1.);
#932=CARTESIAN_POINT('',(-27.02814,1.5748,45.72));
#933=LINE('',#932,#931);
#934=EDGE_CURVE('E314',#902,#927,#933,.F.);
#935=ORIENTED_EDGE('',*,*,#934,.F.);
#936=ORIENTED_EDGE('',*,*,#903,.F.);
#937=EDGE_LOOP('',(#921,#929,#935,#936));
#938=FACE_BOUND('',#937,.T.);
#939=ADVANCED_FACE('F492',(#938),#920,.F.);
#940=CARTESIAN_POINT('',(-39.99992,1.5748,-45.72));
#941=DIRECTION('',(0.,0.,1.));
#942=DIRECTION('',(1.,0.,0.));
#943=AXIS2_PLACEMENT_3D('',#940,#941,#942);
#944=PLANE('',#943);
#945=ORIENTED_EDGE('',*,*,#928,.F.);
#946=ORIENTED_EDGE('',*,*,#139,.F.);
#947=DIRECTION('',(0.,1.,0.));
#948=VECTOR('',#947,1.);
#949=CARTESIAN_POINT('',(-35.49142,-0.9652,-45.72));
#950=LINE('',#949,#948);
#951=CARTESIAN_POINT('',(-35.49142,1.5748,-45.72));
#952=VERTEX_POINT('',#951);
#953=EDGE_CURVE('E257',#130,#952,#950,.T.);
#954=ORIENTED_EDGE('',*,*,#953,.T.);
#955=DIRECTION('',(1.,0.,0.));
#956=VECTOR('',#955,1.);
#957=CARTESIAN_POINT('',(-39.99992,1.5748,-45.72));
#958=LINE('',#957,#956);
#959=EDGE_CURVE('E857',#927,#952,#958,.F.);
#960=ORIENTED_EDGE('',*,*,#959,.F.);
#961=EDGE_LOOP('',(#945,#946,#954,#960));
#962=FACE_BOUND('',#961,.T.);
#963=ADVANCED_FACE('F488',(#962),#944,.F.);
#964=CARTESIAN_POINT('',(-35.49142,-0.9652,-49.0443285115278));
#965=DIRECTION('',(1.,0.,0.));
#966=DIRECTION('',(0.,0.,-1.));
#967=AXIS2_PLACEMENT_3D('',#964,#965,#966);
#968=PLANE('',#967);
#969=ORIENTED_EDGE('',*,*,#131,.F.);
#970=DIRECTION('',(0.,1.,0.));
#971=VECTOR('',#970,1.);
#972=CARTESIAN_POINT('',(-35.49142,-0.9652,-43.815));
#973=LINE('',#972,#971);
#974=CARTESIAN_POINT('',(-35.49142,1.5748,-43.815));
#975=VERTEX_POINT('',#974);
#976=EDGE_CURVE('E252',#122,#975,#973,.T.);
#977=ORIENTED_EDGE('',*,*,#976,.T.);
#978=DIRECTION('',(0.,0.,1.));
#979=VECTOR('',#978,1.);
#980=CARTESIAN_POINT('',(-35.49142,1.5748,45.72));
#981=LINE('',#980,#979);
#982=EDGE_CURVE('E311',#952,#975,#981,.T.);
#983=ORIENTED_EDGE('',*,*,#982,.F.);
#984=ORIENTED_EDGE('',*,*,#953,.F.);
#985=EDGE_LOOP('',(#969,#977,#983,#984));
#986=FACE_BOUND('',#985,.T.);
#987=ADVANCED_FACE('F484',(#986),#968,.F.);
#988=CARTESIAN_POINT('',(-38.09492,-0.9652,-43.815));
#989=DIRECTION('',(0.,1.,0.));
#990=DIRECTION('',(0.,0.,1.));
#991=AXIS2_PLACEMENT_3D('',#988,#989,#990);
#992=CYLINDRICAL_SURFACE('',#991,2.6035);
#993=ORIENTED_EDGE('',*,*,#123,.F.);
#994=DIRECTION('',(0.,1.,0.));
#995=VECTOR('',#994,1.);
#996=CARTESIAN_POINT('',(-38.09492,-0.9652,-41.2115));
#997=LINE('',#996,#995);
#998=CARTESIAN_POINT('',(-38.09492,1.5748,-41.2115));
#999=VERTEX_POINT('',#998);
#1000=EDGE_CURVE('E251',#113,#999,#997,.T.);
#1001=ORIENTED_EDGE('',*,*,#1000,.T.);
#1002=CARTESIAN_POINT('',(-38.09492,1.5748,-43.815));
#1003=DIRECTION('',(0.,1.,0.));
#1004=DIRECTION('',(0.,0.,1.));
#1005=AXIS2_PLACEMENT_3D('',#1002,#1003,#1004);
#1006=CIRCLE('',#1005,2.6035);
#1007=EDGE_CURVE('E307',#975,#999,#1006,.F.);
#1008=ORIENTED_EDGE('',*,*,#1007,.F.);
#1009=ORIENTED_EDGE('',*,*,#976,.F.);
#1010=EDGE_LOOP('',(#993,#1001,#1008,#1009));
#1011=FACE_BOUND('',#1010,.T.);
#1012=ADVANCED_FACE('F480',(#1011),#992,.F.);
#1013=CARTESIAN_POINT('',(-38.09492,-0.9652,-41.2115));
#1014=DIRECTION('',(0.,0.,1.));
#1015=DIRECTION('',(1.,0.,0.));
#1016=AXIS2_PLACEMENT_3D('',#1013,#1014,#1015);
#1017=PLANE('',#1016);
#1018=ORIENTED_EDGE('',*,*,#114,.F.);
#1019=DIRECTION('',(0.,1.,0.));
#1020=VECTOR('',#1019,1.);
#1021=CARTESIAN_POINT('',(-39.99992,1.5748,-41.2115));
#1022=LINE('',#1021,#1020);
#1023=CARTESIAN_POINT('',(-39.99992,1.5748,-41.2115));
#1024=VERTEX_POINT('',#1023);
#1025=EDGE_CURVE('E246',#105,#1024,#1022,.T.);
#1026=ORIENTED_EDGE('',*,*,#1025,.T.);
#1027=DIRECTION('',(1.,0.,0.));
#1028=VECTOR('',#1027,1.);
#1029=CARTESIAN_POINT('',(-39.99992,1.5748,-41.2115));
#1030=LINE('',#1029,#1028);
#1031=EDGE_CURVE('E310',#999,#1024,#1030,.F.);
#1032=ORIENTED_EDGE('',*,*,#1031,.F.);
#1033=ORIENTED_EDGE('',*,*,#1000,.F.);
#1034=EDGE_LOOP('',(#1018,#1026,#1032,#1033));
#1035=FACE_BOUND('',#1034,.T.);
#1036=ADVANCED_FACE('F476',(#1035),#1017,.F.);
#1037=CARTESIAN_POINT('',(-39.99992,1.5748,-45.72));
#1038=DIRECTION('',(1.,0.,0.));
#1039=DIRECTION('',(0.,0.,-1.));
#1040=AXIS2_PLACEMENT_3D('',#1037,#1038,#1039);
#1041=PLANE('',#1040);
#1042=DIRECTION('',(0.,1.,0.));
#1043=VECTOR('',#1042,1.);
#1044=CARTESIAN_POINT('',(-39.99992,-0.9652,40.5765));
#1045=LINE('',#1044,#1043);
#1046=CARTESIAN_POINT('',(-39.99992,1.5748,40.5765));
#1047=VERTEX_POINT('',#1046);
#1048=EDGE_CURVE('E240',#97,#1047,#1045,.T.);
#1049=ORIENTED_EDGE('',*,*,#1048,.T.);
#1050=DIRECTION('',(0.,0.,1.));
#1051=VECTOR('',#1050,1.);
#1052=CARTESIAN_POINT('',(-39.99992,1.5748,45.72));
#1053=LINE('',#1052,#1051);
#1054=EDGE_CURVE('E870',#1024,#1047,#1053,.T.);
#1055=ORIENTED_EDGE('',*,*,#1054,.F.);
#1056=ORIENTED_EDGE('',*,*,#1025,.F.);
#1057=ORIENTED_EDGE('',*,*,#106,.F.);
#1058=EDGE_LOOP('',(#1049,#1055,#1056,#1057));
#1059=FACE_BOUND('',#1058,.T.);
#1060=ADVANCED_FACE('F472',(#1059),#1041,.F.);
#1061=CARTESIAN_POINT('',(-43.8329095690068,-0.9652,40.5765));
#1062=DIRECTION('',(0.,0.,-1.));
#1063=DIRECTION('',(-1.,0.,0.));
#1064=AXIS2_PLACEMENT_3D('',#1061,#1062,#1063);
#1065=PLANE('',#1064);
#1066=ORIENTED_EDGE('',*,*,#98,.F.);
#1067=DIRECTION('',(0.,1.,0.));
#1068=VECTOR('',#1067,1.);
#1069=CARTESIAN_POINT('',(-38.09492,-0.9652,40.5765));
#1070=LINE('',#1069,#1068);
#1071=CARTESIAN_POINT('',(-38.09492,1.5748,40.5765));
#1072=VERTEX_POINT('',#1071);
#1073=EDGE_CURVE('E235',#89,#1072,#1070,.T.);
#1074=ORIENTED_EDGE('',*,*,#1073,.T.);
#1075=DIRECTION('',(1.,0.,0.));
#1076=VECTOR('',#1075,1.);
#1077=CARTESIAN_POINT('',(-39.99992,1.5748,40.5765));
#1078=LINE('',#1077,#1076);
#1079=EDGE_CURVE('E306',#1047,#1072,#1078,.T.);
#1080=ORIENTED_EDGE('',*,*,#1079,.F.);
#1081=ORIENTED_EDGE('',*,*,#1048,.F.);
#1082=EDGE_LOOP('',(#1066,#1074,#1080,#1081));
#1083=FACE_BOUND('',#1082,.T.);
#1084=ADVANCED_FACE('F468',(#1083),#1065,.F.);
#1085=CARTESIAN_POINT('',(-38.09492,-0.9652,43.18));
#1086=DIRECTION('',(0.,1.,0.));
#1087=DIRECTION('',(0.,0.,1.));
#1088=AXIS2_PLACEMENT_3D('',#1085,#1086,#1087);
#1089=CYLINDRICAL_SURFACE('',#1088,2.6035);
#1090=ORIENTED_EDGE('',*,*,#90,.F.);
#1091=DIRECTION('',(0.,1.,0.));
#1092=VECTOR('',#1091,1.);
#1093=CARTESIAN_POINT('',(-35.49142,-0.9652,43.18));
#1094=LINE('',#1093,#1092);
#1095=CARTESIAN_POINT('',(-35.49142,1.5748,43.18));
#1096=VERTEX_POINT('',#1095);
#1097=EDGE_CURVE('E234',#80,#1096,#1094,.T.);
#1098=ORIENTED_EDGE('',*,*,#1097,.T.);
#1099=CARTESIAN_POINT('',(-38.09492,1.5748,43.18));
#1100=DIRECTION('',(0.,1.,0.));
#1101=DIRECTION('',(0.,0.,1.));
#1102=AXIS2_PLACEMENT_3D('',#1099,#1100,#1101);
#1103=CIRCLE('',#1102,2.6035);
#1104=EDGE_CURVE('E302',#1072,#1096,#1103,.F.);
#1105=ORIENTED_EDGE('',*,*,#1104,.F.);
#1106=ORIENTED_EDGE('',*,*,#1073,.F.);
#1107=EDGE_LOOP('',(#1090,#1098,#1105,#1106));
#1108=FACE_BOUND('',#1107,.T.);
#1109=ADVANCED_FACE('F464',(#1108),#1089,.F.);
#1110=CARTESIAN_POINT('',(-35.49142,-0.9652,43.18));
#1111=DIRECTION('',(1.,0.,0.));
#1112=DIRECTION('',(0.,0.,-1.));
#1113=AXIS2_PLACEMENT_3D('',#1110,#1111,#1112);
#1114=PLANE('',#1113);
#1115=ORIENTED_EDGE('',*,*,#81,.F.);
#1116=DIRECTION('',(0.,1.,0.));
#1117=VECTOR('',#1116,1.);
#1118=CARTESIAN_POINT('',(-35.49142,1.5748,45.72));
#1119=LINE('',#1118,#1117);
#1120=CARTESIAN_POINT('',(-35.49142,1.5748,45.72));
#1121=VERTEX_POINT('',#1120);
#1122=EDGE_CURVE('E229',#72,#1121,#1119,.T.);
#1123=ORIENTED_EDGE('',*,*,#1122,.T.);
#1124=DIRECTION('',(0.,0.,1.));
#1125=VECTOR('',#1124,1.);
#1126=CARTESIAN_POINT('',(-35.49142,1.5748,45.72));
#1127=LINE('',#1126,#1125);
#1128=EDGE_CURVE('E305',#1096,#1121,#1127,.T.);
#1129=ORIENTED_EDGE('',*,*,#1128,.F.);
#1130=ORIENTED_EDGE('',*,*,#1097,.F.);
#1131=EDGE_LOOP('',(#1115,#1123,#1129,#1130));
#1132=FACE_BOUND('',#1131,.T.);
#1133=ADVANCED_FACE('F460',(#1132),#1114,.F.);
#1134=CARTESIAN_POINT('',(-39.99992,1.5748,45.72));
#1135=DIRECTION('',(0.,0.,-1.));
#1136=DIRECTION('',(-1.,0.,0.));
#1137=AXIS2_PLACEMENT_3D('',#1134,#1135,#1136);
#1138=PLANE('',#1137);
#1139=DIRECTION('',(0.,1.,0.));
#1140=VECTOR('',#1139,1.);
#1141=CARTESIAN_POINT('',(35.49142,-0.9652,45.72));
#1142=LINE('',#1141,#1140);
#1143=CARTESIAN_POINT('',(35.49142,1.5748,45.72));
#1144=VERTEX_POINT('',#1143);
#1145=EDGE_CURVE('E223',#64,#1144,#1142,.T.);
#1146=ORIENTED_EDGE('',*,*,#1145,.T.);
#1147=DIRECTION('',(1.,0.,0.));
#1148=VECTOR('',#1147,1.);
#1149=CARTESIAN_POINT('',(-39.99992,1.5748,45.72));
#1150=LINE('',#1149,#1148);
#1151=EDGE_CURVE('E883',#1121,#1144,#1150,.T.);
#1152=ORIENTED_EDGE('',*,*,#1151,.F.);
#1153=ORIENTED_EDGE('',*,*,#1122,.F.);
#1154=ORIENTED_EDGE('',*,*,#73,.F.);
#1155=EDGE_LOOP('',(#1146,#1152,#1153,#1154));
#1156=FACE_BOUND('',#1155,.T.);
#1157=ADVANCED_FACE('F456',(#1156),#1138,.F.);
#1158=CARTESIAN_POINT('',(35.49142,-0.9652,43.18));
#1159=DIRECTION('',(-1.,0.,0.));
#1160=DIRECTION('',(0.,0.,1.));
#1161=AXIS2_PLACEMENT_3D('',#1158,#1159,#1160);
#1162=PLANE('',#1161);
#1163=ORIENTED_EDGE('',*,*,#65,.F.);
#1164=DIRECTION('',(0.,1.,0.));
#1165=VECTOR('',#1164,1.);
#1166=CARTESIAN_POINT('',(35.49142,-0.9652,43.18));
#1167=LINE('',#1166,#1165);
#1168=CARTESIAN_POINT('',(35.49142,1.5748,43.18));
#1169=VERTEX_POINT('',#1168);
#1170=EDGE_CURVE('E218',#56,#1169,#1167,.T.);
#1171=ORIENTED_EDGE('',*,*,#1170,.T.);
#1172=DIRECTION('',(0.,0.,1.));
#1173=VECTOR('',#1172,1.);
#1174=CARTESIAN_POINT('',(35.49142,1.5748,45.72));
#1175=LINE('',#1174,#1173);
#1176=EDGE_CURVE('E301',#1144,#1169,#1175,.F.);
#1177=ORIENTED_EDGE('',*,*,#1176,.F.);
#1178=ORIENTED_EDGE('',*,*,#1145,.F.);
#1179=EDGE_LOOP('',(#1163,#1171,#1177,#1178));
#1180=FACE_BOUND('',#1179,.T.);
#1181=ADVANCED_FACE('F452',(#1180),#1162,.F.);
#1182=CARTESIAN_POINT('',(38.09492,-0.9652,43.18));
#1183=DIRECTION('',(0.,1.,0.));
#1184=DIRECTION('',(0.,0.,1.));
#1185=AXIS2_PLACEMENT_3D('',#1182,#1183,#1184);
#1186=CYLINDRICAL_SURFACE('',#1185,2.6035);
#1187=ORIENTED_EDGE('',*,*,#57,.F.);
#1188=DIRECTION('',(0.,1.,0.));
#1189=VECTOR('',#1188,1.);
#1190=CARTESIAN_POINT('',(38.09492,-0.9652,40.5765));
#1191=LINE('',#1190,#1189);
#1192=CARTESIAN_POINT('',(38.09492,1.5748,40.5765));
#1193=VERTEX_POINT('',#1192);
#1194=EDGE_CURVE('E209',#47,#1193,#1191,.T.);
#1195=ORIENTED_EDGE('',*,*,#1194,.T.);
#1196=CARTESIAN_POINT('',(38.09492,1.5748,43.18));
#1197=DIRECTION('',(0.,1.,0.));
#1198=DIRECTION('',(0.,0.,1.));
#1199=AXIS2_PLACEMENT_3D('',#1196,#1197,#1198);
#1200=CIRCLE('',#1199,2.6035);
#1201=EDGE_CURVE('E297',#1169,#1193,#1200,.F.);
#1202=ORIENTED_EDGE('',*,*,#1201,.F.);
#1203=ORIENTED_EDGE('',*,*,#1170,.F.);
#1204=EDGE_LOOP('',(#1187,#1195,#1202,#1203));
#1205=FACE_BOUND('',#1204,.T.);
#1206=ADVANCED_FACE('F448',(#1205),#1186,.F.);
#1207=CARTESIAN_POINT('',(44.3342036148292,-0.9652,40.5765));
#1208=DIRECTION('',(0.,0.,-1.));
#1209=DIRECTION('',(-1.,0.,0.));
#1210=AXIS2_PLACEMENT_3D('',#1207,#1208,#1209);
#1211=PLANE('',#1210);
#1212=ORIENTED_EDGE('',*,*,#48,.F.);
#1213=DIRECTION('',(0.,1.,0.));
#1214=VECTOR('',#1213,1.);
#1215=CARTESIAN_POINT('',(39.99992,1.5748,40.5765));
#1216=LINE('',#1215,#1214);
#1217=CARTESIAN_POINT('',(39.99992,1.5748,40.5765));
#1218=VERTEX_POINT('',#1217);
#1219=EDGE_CURVE('E208',#39,#1218,#1216,.T.);
#1220=ORIENTED_EDGE('',*,*,#1219,.T.);
#1221=DIRECTION('',(1.,0.,0.));
#1222=VECTOR('',#1221,1.);
#1223=CARTESIAN_POINT('',(-39.99992,1.5748,40.5765));
#1224=LINE('',#1223,#1222);
#1225=EDGE_CURVE('E300',#1193,#1218,#1224,.T.);
#1226=ORIENTED_EDGE('',*,*,#1225,.F.);
#1227=ORIENTED_EDGE('',*,*,#1194,.F.);
#1228=EDGE_LOOP('',(#1212,#1220,#1226,#1227));
#1229=FACE_BOUND('',#1228,.T.);
#1230=ADVANCED_FACE('F445',(#1229),#1211,.F.);
#1231=CARTESIAN_POINT('',(39.99992,1.5748,-45.72));
#1232=DIRECTION('',(-1.,0.,0.));
#1233=DIRECTION('',(0.,0.,1.));
#1234=AXIS2_PLACEMENT_3D('',#1231,#1232,#1233);
#1235=PLANE('',#1234);
#1236=ORIENTED_EDGE('',*,*,#1219,.F.);
#1237=ORIENTED_EDGE('',*,*,#40,.F.);
#1238=DIRECTION('',(0.,1.,0.));
#1239=VECTOR('',#1238,1.);
#1240=CARTESIAN_POINT('',(39.99992,-0.9652,-41.2115));
#1241=LINE('',#1240,#1239);
#1242=CARTESIAN_POINT('',(39.99992,1.5748,-41.2115));
#1243=VERTEX_POINT('',#1242);
#1244=EDGE_CURVE('E35',#31,#1243,#1241,.T.);
#1245=ORIENTED_EDGE('',*,*,#1244,.T.);
#1246=DIRECTION('',(0.,0.,1.));
#1247=VECTOR('',#1246,1.);
#1248=CARTESIAN_POINT('',(39.99992,1.5748,45.72));
#1249=LINE('',#1248,#1247);
#1250=EDGE_CURVE('E26',#1218,#1243,#1249,.F.);
#1251=ORIENTED_EDGE('',*,*,#1250,.F.);
#1252=EDGE_LOOP('',(#1236,#1237,#1245,#1251));
#1253=FACE_BOUND('',#1252,.T.);
#1254=ADVANCED_FACE('F437',(#1253),#1235,.F.);
#1255=CARTESIAN_POINT('',(38.09492,-0.9652,-41.2115));
#1256=DIRECTION('',(0.,0.,1.));
#1257=DIRECTION('',(1.,0.,0.));
#1258=AXIS2_PLACEMENT_3D('',#1255,#1256,#1257);
#1259=PLANE('',#1258);
#1260=ORIENTED_EDGE('',*,*,#32,.F.);
#1261=ORIENTED_EDGE('',*,*,#717,.F.);
#1262=DIRECTION('',(1.,0.,0.));
#1263=VECTOR('',#1262,1.);
#1264=CARTESIAN_POINT('',(-39.99992,1.5748,-41.2115));
#1265=LINE('',#1264,#1263);
#1266=EDGE_CURVE('E11',#1243,#710,#1265,.F.);
#1267=ORIENTED_EDGE('',*,*,#1266,.F.);
#1268=ORIENTED_EDGE('',*,*,#1244,.F.);
#1269=EDGE_LOOP('',(#1260,#1261,#1267,#1268));
#1270=FACE_BOUND('',#1269,.T.);
#1271=ADVANCED_FACE('F430',(#1270),#1259,.F.);
#1272=CARTESIAN_POINT('',(-39.99992,1.5748,45.72));
#1273=DIRECTION('',(0.,1.,0.));
#1274=DIRECTION('',(0.,0.,1.));
#1275=AXIS2_PLACEMENT_3D('',#1272,#1273,#1274);
#1276=PLANE('',#1275);
#1277=ORIENTED_EDGE('',*,*,#1250,.T.);
#1278=ORIENTED_EDGE('',*,*,#1266,.T.);
#1279=ORIENTED_EDGE('',*,*,#711,.T.);
#1280=ORIENTED_EDGE('',*,*,#739,.T.);
#1281=ORIENTED_EDGE('',*,*,#763,.T.);
#1282=ORIENTED_EDGE('',*,*,#788,.T.);
#1283=ORIENTED_EDGE('',*,*,#813,.T.);
#1284=ORIENTED_EDGE('',*,*,#837,.T.);
#1285=ORIENTED_EDGE('',*,*,#862,.T.);
#1286=ORIENTED_EDGE('',*,*,#885,.T.);
#1287=ORIENTED_EDGE('',*,*,#910,.T.);
#1288=ORIENTED_EDGE('',*,*,#934,.T.);
#1289=ORIENTED_EDGE('',*,*,#959,.T.);
#1290=ORIENTED_EDGE('',*,*,#982,.T.);
#1291=ORIENTED_EDGE('',*,*,#1007,.T.);
#1292=ORIENTED_EDGE('',*,*,#1031,.T.);
#1293=ORIENTED_EDGE('',*,*,#1054,.T.);
#1294=ORIENTED_EDGE('',*,*,#1079,.T.);
#1295=ORIENTED_EDGE('',*,*,#1104,.T.);
#1296=ORIENTED_EDGE('',*,*,#1128,.T.);
#1297=ORIENTED_EDGE('',*,*,#1151,.T.);
#1298=ORIENTED_EDGE('',*,*,#1176,.T.);
#1299=ORIENTED_EDGE('',*,*,#1201,.T.);
#1300=ORIENTED_EDGE('',*,*,#1225,.T.);
#1301=EDGE_LOOP('',(#1277,#1278,#1279,#1280,#1281,#1282,#1283,#1284,#1285,#1286,#1287,#1288,
#1289,#1290,#1291,#1292,#1293,#1294,#1295,#1296,#1297,#1298,#1299,#1300));
#1302=FACE_BOUND('',#1301,.T.);
#1303=ORIENTED_EDGE('',*,*,#685,.T.);
#1304=EDGE_LOOP('',(#1303));
#1305=FACE_BOUND('',#1304,.T.);
#1306=ORIENTED_EDGE('',*,*,#665,.T.);
#1307=EDGE_LOOP('',(#1306));
#1308=FACE_BOUND('',#1307,.T.);
#1309=ORIENTED_EDGE('',*,*,#645,.T.);
#1310=EDGE_LOOP('',(#1309));
#1311=FACE_BOUND('',#1310,.T.);
#1312=ORIENTED_EDGE('',*,*,#625,.T.);
#1313=EDGE_LOOP('',(#1312));
#1314=FACE_BOUND('',#1313,.T.);
#1315=ORIENTED_EDGE('',*,*,#605,.T.);
#1316=EDGE_LOOP('',(#1315));
#1317=FACE_BOUND('',#1316,.T.);
#1318=ORIENTED_EDGE('',*,*,#585,.T.);
#1319=EDGE_LOOP('',(#1318));
#1320=FACE_BOUND('',#1319,.T.);
#1321=ORIENTED_EDGE('',*,*,#565,.T.);
#1322=EDGE_LOOP('',(#1321));
#1323=FACE_BOUND('',#1322,.T.);
#1324=ORIENTED_EDGE('',*,*,#545,.T.);
#1325=EDGE_LOOP('',(#1324));
#1326=FACE_BOUND('',#1325,.T.);
#1327=ORIENTED_EDGE('',*,*,#525,.T.);
#1328=EDGE_LOOP('',(#1327));
#1329=FACE_BOUND('',#1328,.T.);
#1330=ORIENTED_EDGE('',*,*,#505,.T.);
#1331=EDGE_LOOP('',(#1330));
#1332=FACE_BOUND('',#1331,.T.);
#1333=ORIENTED_EDGE('',*,*,#485,.T.);
#1334=EDGE_LOOP('',(#1333));
#1335=FACE_BOUND('',#1334,.T.);
#1336=ORIENTED_EDGE('',*,*,#465,.T.);
#1337=EDGE_LOOP('',(#1336));
#1338=FACE_BOUND('',#1337,.T.);
#1339=ORIENTED_EDGE('',*,*,#445,.T.);
#1340=EDGE_LOOP('',(#1339));
#1341=FACE_BOUND('',#1340,.T.);
#1342=ORIENTED_EDGE('',*,*,#425,.T.);
#1343=EDGE_LOOP('',(#1342));
#1344=FACE_BOUND('',#1343,.T.);
#1345=ORIENTED_EDGE('',*,*,#405,.T.);
#1346=EDGE_LOOP('',(#1345));
#1347=FACE_BOUND('',#1346,.T.);
#1348=ADVANCED_FACE('F428',(#1302,#1305,#1308,#1311,#1314,#1317,#1320,#1323,#1326,#1329,#1332,
#1335,#1338,#1341,#1344,#1347),#1276,.T.);
#1349=CLOSED_SHELL('',(#389,#409,#429,#449,#469,#489,#509,#529,#549,#569,#589,#609,#629,#649,
#669,#689,#721,#745,#769,#793,#818,#842,#866,#890,#915,#939,#963,#987,#1012,#1036,#1060,#1084,
#1109,#1133,#1157,#1181,#1206,#1230,#1254,#1271,#1348));
#1350=MANIFOLD_SOLID_BREP('B1',#1349);
#1351=ADVANCED_BREP_SHAPE_REPRESENTATION('',(#18,#1350),#14);
#1352=SHAPE_DEFINITION_REPRESENTATION(#9,#1351);
ENDSEC;
END-ISO-10303-21;
